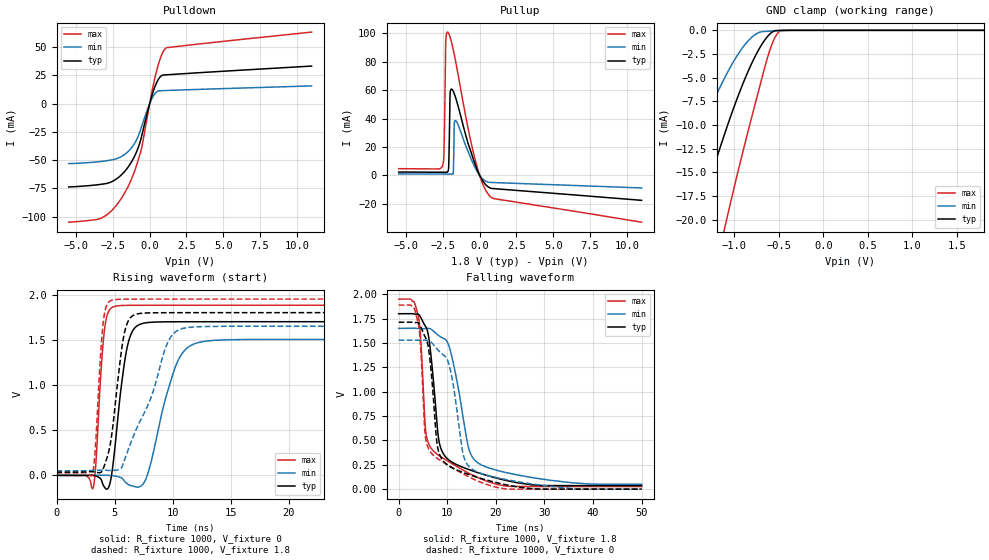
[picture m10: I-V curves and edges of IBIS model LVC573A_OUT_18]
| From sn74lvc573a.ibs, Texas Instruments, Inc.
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[Model]   LVC573A_OUT_18
Model_type  3-state
Enable   Active-Low
Vref =   0
Rref =   1000
Cref =   30p
Vmeas =   0.9
| variable   typ   min   max
C_comp   2.80pF   2.60pF   3.07pF
| C_pullup   4.30pF   3.38pF   4.99pF
| C_pulldown   4.80pF   2.51pF   7.32pF
| C_tri-state   2.80pF   2.60pF   3.07pF
[Temperature Range]   40   100   -40
| Ambient temperature   25   85   -40
[Voltage range]   1.8   1.65   1.95
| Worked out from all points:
|   slope of the pulldown table from 0 to 0.27 V, typ, clamps not added: 22.7 ohm
|   slope of the pullup table from 0 to 0.27 V, typ, clamps not added: 57.2 ohm
|   GND clamp passes 1 mA (typ) near -0.66 V on its own axis
|   rising waveform, R_fixture 1000, V_fixture 0: 20-80 % time 945ps typ, 1.83ns min, 542ps max; typ from 0 V to 1.7 V
|   falling waveform, R_fixture 1000, V_fixture 1.8: 20-80 % time 2.45ns typ, 3.66ns min, 2.31ns max; typ from 1.8 V to 0.036 V
|   rising waveform, R_fixture 1000, V_fixture 1.8: 20-80 % time 983ps typ, 2.75ns min, 532ps max; typ from 0.036 V to 1.8 V
|   falling waveform, R_fixture 1000, V_fixture 0: 20-80 % time 2.19ns typ, 2.95ns min, 2.17ns max; typ from 1.71 V to 0 V
[GND Clamp]
| LVC573A_OUT_18
|   Voltage   I(typ)   I(min)   I(max)
-5.5V     -186.1mA   -140.6mA   -253.4mA
-1.805V   -33.67mA   -21.47mA   -52.5mA
-1.745V   -31.52mA   -19.85mA   -49.6mA
-1.415V   -20.27mA   -11.52mA   -34.18mA
-1.135V   -11.68mA   -5.515mA   -22mA
-1.095V   -10.55mA   -4.772mA   -20.34mA
-920mV    -6.023mA   -1.998mA   -13.43mA
-760mV    -2.632mA   -411.6uA   -7.56mA
-605mV    -425uA     -92.11uA   -2.195mA
-545mV    -47.88uA   -63.87uA   -778.6uA
-490mV    -7.657uA   -40.92uA   -89.17uA
1.8V      11.85pA    18.98nA    148.1pA
[Pulldown]
| LVC573A_OUT_18
|   Voltage   I(typ)   I(min)   I(max)
-5.5V     -73.69mA   -53.03mA   -104.9mA
-3.175V   -71.1mA    -50.93mA   -100.5mA
-2.405V   -67.85mA   -49.26mA   -92.18mA
-1.67V    -59.55mA   -44.64mA   -78.33mA
-1.05V    -47.11mA   -35.63mA   -60.67mA
-615mV    -32.29mA   -22.88mA   -42.88mA
-485mV    -25.5mA    -17.87mA   -35.46mA
5mV       248.2uA    163.4uA    357.1uA
360mV     15.11mA    8.927mA    23.08mA
745mV     24.2mA     11.51mA    40.9mA
1.095V    25.54mA    11.68mA    49.09mA
11V       33.33mA    15.76mA    63.4mA
[Pullup]
| LVC573A_OUT_18
|   Voltage   I(typ)   I(min)   I(max)
-5.5V     2.385mA    1.055mA    4.758mA
-2.515V   2.247mA    990.6uA    7.072mA
-2.425V   2.241mA    988.2uA    15.69mA
-2.305V   2.238mA    984.8uA    93.33mA
-2.175V   2.566mA    980.9uA    100.7mA
-2.1V     7.892mA    978.5uA    99.79mA
-2.01V    57.13mA    975.2uA    97.32mA
-1.905V   60.71mA    970.8uA    93.37mA
-1.795V   59.15mA    1.403mA    88.43mA
-1.65V    55.2mA     38.53mA    81.12mA
700mV     -8.757mA   -4.895mA   -14.65mA
11V       -17.49mA   -8.793mA   -32.85mA
[Ramp]
| LVC573A_OUT_18
| variable   typ   min   max
dV/dt_r   1.11/1.00E-09   0.98/1.94E-09   1.22/5.76E-10
dV/dt_f   1.06/2.44E-09   0.96/3.66E-09   1.15/2.31E-09
R_load = 1000
[Rising Waveform]
| LVC573A_OUT_18
R_fixture =   1000
C_fixture =   0
L_fixture =   0
V_fixture =   0
V_fixture_min = 0
V_fixture_max = 0
|   Time   V(typ)   V(min)   V(max)
0s        181.4pV    6.737nV    1.594nV
3.155ns   -186.1uV   -496.2uV   -138.3mV
4.11ns    -127mV     958.4uV    1.586V
4.565ns   -106.5mV   -918.1uV   1.831V
4.98ns    248.7mV    -5.757mV   1.868V
6.1ns     1.425V     -93.94mV   1.88V
7.42ns    1.681V     -102mV     1.881V
10.26ns   1.699V     1.208V     1.882V
12.11ns   1.699V     1.466V     1.882V
50ns      1.7V       1.505V     1.882V
[Falling Waveform]
| LVC573A_OUT_18
R_fixture =   1000
C_fixture =   0
L_fixture =   0
V_fixture =   1.8
V_fixture_min = 1.65
V_fixture_max = 1.95
|   Time   V(typ)   V(min)   V(max)
0s        1.8V       1.65V      1.95V
3.995ns   1.796V     1.649V     1.787V
5.605ns   1.665V     1.649V     579.1mV
6.475ns   1.45V      1.646V     435.6mV
7.78ns    739.3mV    1.594V     363.9mV
9.44ns    344.7mV    1.542V     308.9mV
11.15ns   272.3mV    1.315V     256.6mV
14.39ns   202.1mV    423.1mV    165mV
16.23ns   170.5mV    272.8mV    120.3mV
50ns      36.17mV    50.98mV    27.13mV
[Rising Waveform]
| LVC573A_OUT_18
R_fixture =   1000
C_fixture =   0
L_fixture =   0
V_fixture =   1.8
V_fixture_min = 1.65
V_fixture_max = 1.95
|   Time   V(typ)   V(min)   V(max)
0s        36.02mV    50.49mV    27.09mV
3.095ns   40.32mV    53.87mV    17.07mV
3.335ns   36.47mV    55.76mV    288.8mV
4.015ns   72.86mV    56.41mV    1.679V
4.77ns    462.2mV    54.45mV    1.937V
5.645ns   1.428V     94.39mV    1.948V
6.225ns   1.718V     299.8mV    1.949V
9.55ns    1.799V     1.461V     1.95V
10.86ns   1.799V     1.625V     1.95V
50ns      1.8V       1.65V      1.95V
[Falling Waveform]
| LVC573A_OUT_18
R_fixture =   1000
C_fixture =   0
L_fixture =   0
V_fixture =   0
V_fixture_min = 0
V_fixture_max = 0
|   Time   V(typ)   V(min)   V(max)
0s        1.713V     1.529V     1.889V
4.05ns    1.706V     1.528V     1.696V
4.57ns    1.663V     1.527V     1.413V
5.355ns   1.572V     1.53V      614.1mV
5.78ns    1.526V     1.527V     465.1mV
7.67ns    576.3mV    1.452V     326.2mV
10.32ns   238.8mV    1.284V     241.2mV
13.25ns   171.1mV    364.7mV    157.2mV
15.13ns   138.4mV    204.6mV    109.4mV
50ns      135.7uV    429.5uV    41.48uV
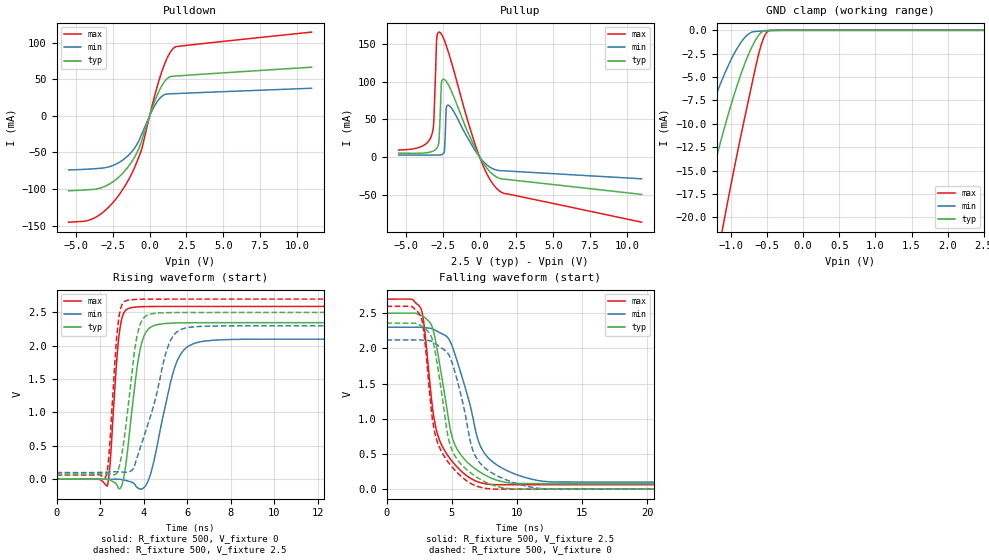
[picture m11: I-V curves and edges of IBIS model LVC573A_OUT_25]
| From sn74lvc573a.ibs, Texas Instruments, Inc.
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[Model]   LVC573A_OUT_25
Model_type  3-state
Enable   Active-Low
Vref =   0
Rref =   500
Cref =   30p
Vmeas =   1.25
| variable   typ   min   max
C_comp   2.70pF   2.52pF   3.01pF
| C_pullup   4.55pF   3.21pF   5.79pF
| C_pulldown   4.50pF   2.35pF   6.70pF
| C_tri-state   2.70pF   2.52pF   3.01pF
[Temperature Range]   40   100   -40
| Ambient temperature   25   85   -40
[Voltage range]   2.5   2.3   2.7
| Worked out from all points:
|   slope of the pulldown table from 0 to 0.375 V, typ, clamps not added: 17.5 ohm
|   slope of the pullup table from 0 to 0.375 V, typ, clamps not added: 32.2 ohm
|   GND clamp passes 1 mA (typ) near -0.66 V on its own axis
|   rising waveform, R_fixture 500, V_fixture 0: 20-80 % time 525ps typ, 864ps min, 324ps max; typ from 0 V to 2.35 V
|   falling waveform, R_fixture 500, V_fixture 2.5: 20-80 % time 1.58ns typ, 2.06ns min, 1.35ns max; typ from 2.5 V to 0.079 V
|   rising waveform, R_fixture 500, V_fixture 2.5: 20-80 % time 541ps typ, 1.08ns min, 317ps max; typ from 0.079 V to 2.5 V
|   falling waveform, R_fixture 500, V_fixture 0: 20-80 % time 1.45ns typ, 1.76ns min, 1.3ns max; typ from 2.36 V to 0 V
[GND Clamp]
| LVC573A_OUT_25
|   Voltage   I(typ)   I(min)   I(max)
-5.5V     -186.1mA   -140.6mA   -253.4mA
-1.83V    -34.56mA   -22.15mA   -53.72mA
-1.765V   -32.23mA   -20.39mA   -50.57mA
-1.43V    -20.76mA   -11.88mA   -34.86mA
-1.28V    -15.99mA   -8.472mA   -28.18mA
-1.105V   -10.83mA   -4.954mA   -20.76mA
-910mV    -5.787mA   -1.867mA   -13.05mA
-750mV    -2.451mA   -354.2uA   -7.201mA
-595mV    -337.1uA   -87.16uA   -1.918mA
-535mV    -26.65uA   -59.48uA   -605.7uA
-485mV    -6.651uA   -39uA      -60.71uA
2.5V      14.06pA    52nA       155pA
[Pulldown]
| LVC573A_OUT_25
|   Voltage   I(typ)   I(min)   I(max)
-5.5V     -102.4mA   -73.99mA   -145.3mA
-4.28V    -101.2mA   -72.98mA   -143.4mA
-3.475V   -99.41mA   -71.9mA    -136.3mA
-2.54V    -90.72mA   -68.23mA   -119.6mA
-1.65V    -74.41mA   -57.76mA   -95mA
-1.025V   -56.45mA   -44.16mA   -70.75mA
-575mV    -36.39mA   -26.9mA    -47.7mA
130mV     7.899mA    5.652mA    10.84mA
580mV     31.19mA    21.07mA    44.55mA
1.155V    50.04mA    29.74mA    77.18mA
1.665V    54.11mA    30.2mA     92.97mA
11V       66.33mA    37.57mA    114.3mA
[Pullup]
| LVC573A_OUT_25
|   Voltage   I(typ)   I(min)   I(max)
-5.5V     5.257mA    2.846mA    9.478mA
-3.265V   7.269mA    2.742mA    28.64mA
-3.11V    8.581mA    2.735mA    48.94mA
-2.92V    11.78mA    2.731mA    156mA
-2.74V    29.33mA    2.835mA    165.3mA
-2.6V     97.53mA    3.262mA    162.7mA
-2.38V    102.5mA    11.04mA    153.6mA
-2.275V   100.3mA    64.02mA    147.9mA
-2.11V    95.11mA    68.5mA     138.1mA
-90mV     3.26mA     2.372mA    4.804mA
1.205V    -26.79mA   -17.37mA   -42.37mA
11V       -49.24mA   -28.58mA   -85.93mA
[Ramp]
| LVC573A_OUT_25
| variable   typ   min   max
dV/dt_r   1.49/5.52E-10   1.35/9.16E-10   1.62/3.36E-10
dV/dt_f   1.45/1.58E-09   1.32/2.06E-09   1.58/1.36E-09
R_load = 500
[Rising Waveform]
| LVC573A_OUT_25
R_fixture =   500
C_fixture =   0
L_fixture =   0
V_fixture =   0
V_fixture_min = 0
V_fixture_max = 0
|   Time   V(typ)   V(min)   V(max)
0s        196.3pV    4.864nV    1.466nV
2.33ns    -1.87mV    -226uV     -101.7mV
2.91ns    -141.1mV   -1.531mV   2.249V
3.155ns   151.3mV    -17.01mV   2.523V
3.505ns   1.148V     -51.92mV   2.575V
3.835ns   1.933V     -147.8mV   2.585V
4.195ns   2.241V     -35.95mV   2.588V
5.515ns   2.342V     1.75V      2.59V
6.795ns   2.346V     2.07V      2.59V
50ns      2.346V     2.1V       2.59V
[Falling Waveform]
| LVC573A_OUT_25
R_fixture =   500
C_fixture =   0
L_fixture =   0
V_fixture =   2.5
V_fixture_min = 2.3
V_fixture_max = 2.7
|   Time   V(typ)   V(min)   V(max)
0s        2.5V       2.3V       2.7V
2.645ns   2.464V     2.3V       2.562V
2.89ns    2.445V     2.295V     2.318V
3.685ns   2.177V     2.264V     963.5mV
4.7ns     1.058V     2.153V     478.1mV
5.43ns    562.5mV    1.811V     311.4mV
7.2ns     238.4mV    611.3mV    92.67mV
9.01ns    100.6mV    284.4mV    63.26mV
12.43ns   78.96mV    105.5mV    62.66mV
50ns      78.81mV    100.4mV    62.58mV
[Rising Waveform]
| LVC573A_OUT_25
R_fixture =   500
C_fixture =   0
L_fixture =   0
V_fixture =   2.5
V_fixture_min = 2.3
V_fixture_max = 2.7
|   Time   V(typ)   V(min)   V(max)
0s        78.72mV    100.2mV    62.56mV
2.265ns   87.03mV    104mV      42.21mV
2.42ns    80.93mV    107mV      409.4mV
2.84ns    147.2mV    110.8mV    2.362V
3.3ns     1.116V     108.1mV    2.684V
3.65ns    2.055V     271.6mV    2.695V
3.96ns    2.398V     581.5mV    2.698V
5.175ns   2.497V     2.032V     2.7V
6.095ns   2.499V     2.276V     2.7V
50ns      2.5V       2.3V       2.7V
[Falling Waveform]
| LVC573A_OUT_25
R_fixture =   500
C_fixture =   0
L_fixture =   0
V_fixture =   0
V_fixture_min = 0
V_fixture_max = 0
|   Time   V(typ)   V(min)   V(max)
0s        2.359V     2.12V      2.597V
2.64ns    2.324V     2.119V     2.449V
2.89ns    2.299V     2.116V     2.188V
3.62ns    2.052V     2.085V     878.8mV
4.66ns    802mV      1.941V     402.2mV
5.395ns   428.7mV    1.565V     240.1mV
6.5ns     224.1mV    624.3mV    77.6mV
7.145ns   144.7mV    376mV      29.42mV
12.24ns   236.2uV    3.538mV    107.2uV
50ns      82.01uV    236.9uV    23.26uV
